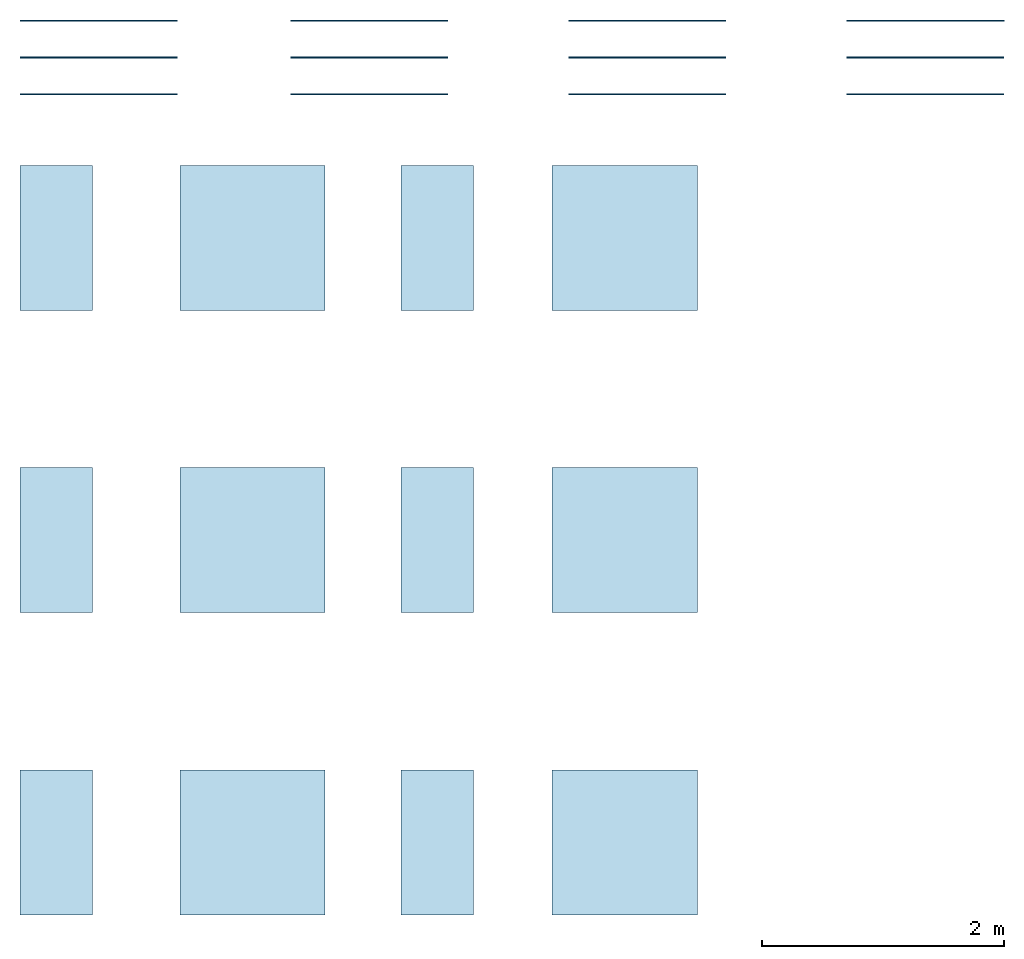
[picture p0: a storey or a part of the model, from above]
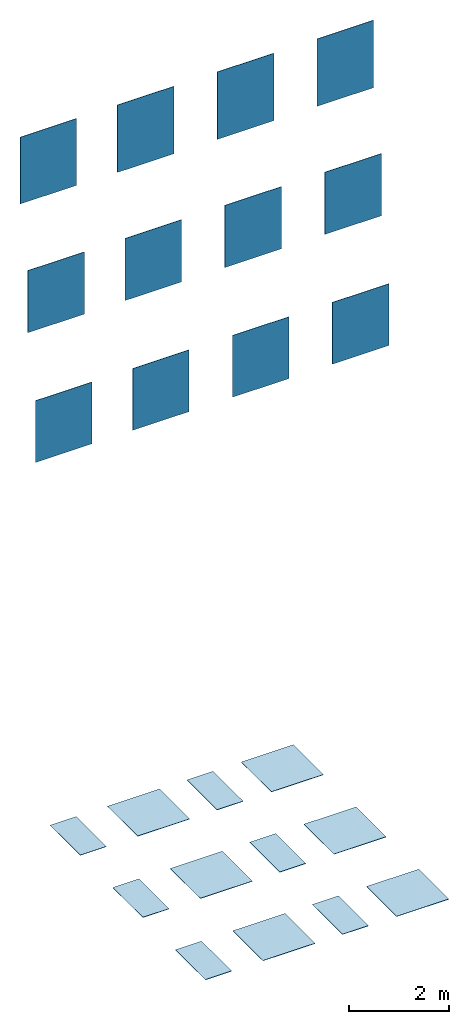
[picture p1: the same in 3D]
Properties of the parts of a building model (IFC2X3)

# File
Description: ViewDefinition [CoordinationView_V2.0], RevitIdentifiers [VersionGUID: 359dbaa7-ac9f-4176-8c9c-8c6b3bc34025, NumberOfSaves: 262], CoordinateReference [CoordinateBase: Shared Coordinates, ProjectSite: Internal]
File name: Project Number
Time: 2024-11-27T16:13:28+01:00
Written by: ODA SDAI 24.3
Made in: Autodesk Revit 24.1.11.26 (ENU) - IFC 24.1.11.26

# IfcProject, Project Number
LongName: Refin-Blended; Phase: Project Status

# IfcSite, Default
RefLatitude: 51, 30, 0, 549316; RefLongitude: 0, -7, -34, -450321; RefElevation: 0 mm

# IfcBuilding
Pset_BuildingCommon - NumberOfStoreys: 1

# IfcBuildingStorey: Level:Circle Head - Project Datum (2)
Pset_AirSideSystemInformation - sets with these values: 2
Name | LongName = Name | Elevation (mm)
Level 0 | Level 0 | 0
Level 1 | Level 1 | 4000

# IfcSlab: Floor:Floor_Tiles_Refin-Cera-Scaglie-Fumo-Cerasilk-120x120 RG00, Floor:Floor_Tiles_Refin-Cera-Scaglie-Fumo-Cerasilk-120x120 RG00:347123
In: Level 0
Type - PredefinedType: FLOOR; Material: Cera-Scaglie-Fumo-Cerasilk-120x120 RG00 9 mm, <Unnamed> 1 mm
Type - Pset_ConcreteElementGeneral - FireRating: INERT
Type - Pset_ElementShading - Color: LIGHT GREY
Type - Pset_FireRatingProperties - SurfaceSpreadOfFlame: INERT
Type - Pset_ManufacturerOccurrence - BarCode: N/A; SerialNumber: N/A
Type - Pset_ManufacturerTypeInformation - ArticleNumber: RG00; ModelReference: RG00; ModelLabel: SCAGLIE FUMO CERASILK R 120X120; Manufacturer: info@refin.it; ProductionYear: N/A
Type - Pset_PrecastConcreteElementGeneral - SerialNumber: N/A
Type - Pset_ProductRequirements - Name: Cera_Scaglie_Fumo_Cerasilk_120X120 R; Category: Pr_35_93_96_19:Ceramic tiles
Type - Pset_QuantityTakeOff - Reference: N/A
Type - Pset_ReinforcementBarPitchOfSlab - Description: PORCELAIN STONEWARE TILE; Reference: N/A
Type - Pset_SlabCommon - Reference: N/A; IsExternal: no; AcousticRating: N/A; FireRating: INERT; SurfaceSpreadOfFlame: INERT
Type - Pset_Warranty - WarrantyContent: N/A; Exclusions: N/A
Pset_QuantityTakeOff - sets with these values: 2
Pset_SlabCommon - LoadBearing: no; PitchAngle: 0 deg

# IfcSlab: Floor:Floor_Tiles_Refin-Cera-Scaglie-Fumo-Cerasilk-60x120 RF40, Floor:Floor_Tiles_Refin-Cera-Scaglie-Fumo-Cerasilk-60x120 RF40:304668
In: Level 0
Type - PredefinedType: FLOOR; Material: Cera-Scaglie-Fumo-Cerasilk-60x120 RF40 9 mm, <Unnamed> 1 mm
Type - Pset_ConcreteElementGeneral - FireRating: INERT
Type - Pset_ElementShading - Color: LIGHT GREY
Type - Pset_FireRatingProperties - SurfaceSpreadOfFlame: INERT
Type - Pset_ManufacturerOccurrence - BarCode: N/A; SerialNumber: N/A
Type - Pset_ManufacturerTypeInformation - ArticleNumber: RF40; ModelReference: RF40; ModelLabel: SCAGLIE FUMO CERASILK R 60X120; Manufacturer: info@refin.it; ProductionYear: N/A
Type - Pset_PrecastConcreteElementGeneral - SerialNumber: N/A
Type - Pset_ProductRequirements - Name: Cera_Scaglie_Fumo_Cerasilk_60X120 R; Category: Pr_35_93_96_19:Ceramic tiles
Type - Pset_QuantityTakeOff - Reference: N/A
Type - Pset_ReinforcementBarPitchOfSlab - Description: PORCELAIN STONEWARE TILE; Reference: N/A
Type - Pset_SlabCommon - Reference: N/A; IsExternal: no; AcousticRating: N/A; FireRating: INERT; SurfaceSpreadOfFlame: INERT
Type - Pset_Warranty - WarrantyContent: N/A; Exclusions: N/A
Pset_QuantityTakeOff - sets with these values: 2
Pset_SlabCommon - LoadBearing: no; PitchAngle: 0 deg

# IfcSlab: Floor:Floor_Tiles_Refin-Cera-Scaglie-Fumo-Matt-Pro-120x120 RG03, Floor:Floor_Tiles_Refin-Cera-Scaglie-Fumo-Matt-Pro-120x120 RG03:347572
In: Level 0
Type - PredefinedType: FLOOR; Material: Cera-Scaglie-Fumo-Matt-Pro-120x120 RG03 9 mm, <Unnamed> 1 mm
Type - Pset_ConcreteElementGeneral - FireRating: INERT
Type - Pset_ElementShading - Color: LIGHT GREY
Type - Pset_FireRatingProperties - SurfaceSpreadOfFlame: INERT
Type - Pset_ManufacturerOccurrence - BarCode: N/A; SerialNumber: N/A
Type - Pset_ManufacturerTypeInformation - ArticleNumber: RG03; ModelReference: RG03; ModelLabel: SCAGLIE FUMO MATT-PRO R 120X120; Manufacturer: info@refin.it; ProductionYear: N/A
Type - Pset_PrecastConcreteElementGeneral - SerialNumber: N/A
Type - Pset_ProductRequirements - Name: Cera_Scaglie_Fumo_Matt_Pro_120X120 R; Category: Pr_35_93_96_19:Ceramic tiles
Type - Pset_QuantityTakeOff - Reference: N/A
Type - Pset_ReinforcementBarPitchOfSlab - Description: PORCELAIN STONEWARE TILE; Reference: N/A
Type - Pset_SlabCommon - Reference: N/A; IsExternal: no; AcousticRating: N/A; FireRating: INERT; SurfaceSpreadOfFlame: INERT
Type - Pset_Warranty - WarrantyContent: N/A; Exclusions: N/A
Pset_QuantityTakeOff - sets with these values: 2
Pset_SlabCommon - LoadBearing: no; PitchAngle: 0 deg

# IfcSlab: Floor:Floor_Tiles_Refin-Cera-Scaglie-Fumo-Matt-Pro-60x120 RG06, Floor:Floor_Tiles_Refin-Cera-Scaglie-Fumo-Matt-Pro-60x120 RG06:347314
In: Level 0
Type - PredefinedType: FLOOR; Material: Cera-Scaglie-Fumo-Matt-Pro-60x120 RG06 9 mm, <Unnamed> 1 mm
Type - Pset_ConcreteElementGeneral - FireRating: INERT
Type - Pset_ElementShading - Color: LIGHT GREY
Type - Pset_FireRatingProperties - SurfaceSpreadOfFlame: INERT
Type - Pset_ManufacturerOccurrence - BarCode: N/A; SerialNumber: N/A
Type - Pset_ManufacturerTypeInformation - ArticleNumber: RG06; ModelReference: RG06; ModelLabel: SCAGLIE FUMO MATT-PRO R 60X120; Manufacturer: info@refin.it; ProductionYear: N/A
Type - Pset_PrecastConcreteElementGeneral - SerialNumber: N/A
Type - Pset_ProductRequirements - Name: Cera_Scaglie_Fumo_Matt_Pro_60X120 R; Category: Pr_35_93_96_19:Ceramic tiles
Type - Pset_QuantityTakeOff - Reference: N/A
Type - Pset_ReinforcementBarPitchOfSlab - Description: PORCELAIN STONEWARE TILE; Reference: N/A
Type - Pset_SlabCommon - Reference: N/A; IsExternal: no; AcousticRating: N/A; FireRating: INERT; SurfaceSpreadOfFlame: INERT
Type - Pset_Warranty - WarrantyContent: N/A; Exclusions: N/A
Pset_QuantityTakeOff - sets with these values: 2
Pset_SlabCommon - LoadBearing: no; PitchAngle: 0 deg

# IfcSlab: Floor:Floor_Tiles_Refin-Cera-Scaglie-Incenso-Cerasilk-120x120 RG01, Floor:Floor_Tiles_Refin-Cera-Scaglie-Incenso-Cerasilk-120x120 RG01:348038
In: Level 0
Type - PredefinedType: FLOOR; Material: Cera-Scaglie-Incenso-Cerasilk-120x120 RG01 9 mm, <Unnamed> 1 mm
Type - Pset_ConcreteElementGeneral - FireRating: INERT
Type - Pset_ElementShading - Color: BEIGE
Type - Pset_FireRatingProperties - SurfaceSpreadOfFlame: INERT
Type - Pset_ManufacturerOccurrence - BarCode: N/A; SerialNumber: N/A
Type - Pset_ManufacturerTypeInformation - ArticleNumber: RG01; ModelReference: RG01; ModelLabel: SCAGLIE INCENSO CERASILK R 120X120; Manufacturer: info@refin.it; ProductionYear: N/A
Type - Pset_PrecastConcreteElementGeneral - SerialNumber: N/A
Type - Pset_ProductRequirements - Name: Cera_Scaglie_Incenso_Cerasilk_120X120 R; Category: Pr_35_93_96_19:Ceramic tiles
Type - Pset_QuantityTakeOff - Reference: N/A
Type - Pset_ReinforcementBarPitchOfSlab - Description: PORCELAIN STONEWARE TILE; Reference: N/A
Type - Pset_SlabCommon - Reference: N/A; IsExternal: no; AcousticRating: N/A; FireRating: INERT; SurfaceSpreadOfFlame: INERT
Type - Pset_Warranty - WarrantyContent: N/A; Exclusions: N/A
Pset_QuantityTakeOff - sets with these values: 2
Pset_SlabCommon - LoadBearing: no; PitchAngle: 0 deg

# IfcSlab: Floor:Floor_Tiles_Refin-Cera-Scaglie-Incenso-Cerasilk-60x120 RF41, Floor:Floor_Tiles_Refin-Cera-Scaglie-Incenso-Cerasilk-60x120 RF41:347870
In: Level 0
Type - PredefinedType: FLOOR; Material: Cera-Scaglie-Incenso-Cerasilk-60x120 RF41 9 mm, <Unnamed> 1 mm
Type - Pset_ConcreteElementGeneral - FireRating: INERT
Type - Pset_ElementShading - Color: BEIGE
Type - Pset_FireRatingProperties - SurfaceSpreadOfFlame: INERT
Type - Pset_ManufacturerOccurrence - BarCode: N/A; SerialNumber: N/A
Type - Pset_ManufacturerTypeInformation - ArticleNumber: RF41; ModelReference: RF41; ModelLabel: SCAGLIE INCENSO CERASILK R 60X120; Manufacturer: info@refin.it; ProductionYear: N/A
Type - Pset_PrecastConcreteElementGeneral - SerialNumber: N/A
Type - Pset_ProductRequirements - Name: Cera_Scaglie_Incenso_Cerasilk_60X120 R; Category: Pr_35_93_96_19:Ceramic tiles
Type - Pset_QuantityTakeOff - Reference: N/A
Type - Pset_ReinforcementBarPitchOfSlab - Description: PORCELAIN STONEWARE TILE; Reference: N/A
Type - Pset_SlabCommon - Reference: N/A; IsExternal: no; AcousticRating: N/A; FireRating: INERT; SurfaceSpreadOfFlame: INERT
Type - Pset_Warranty - WarrantyContent: N/A; Exclusions: N/A
Pset_QuantityTakeOff - sets with these values: 2
Pset_SlabCommon - LoadBearing: no; PitchAngle: 0 deg

# IfcSlab: Floor:Floor_Tiles_Refin-Cera-Scaglie-Incenso-Matt-Pro-120x120 RG04, Floor:Floor_Tiles_Refin-Cera-Scaglie-Incenso-Matt-Pro-120x120 RG04:348478
In: Level 0
Type - PredefinedType: FLOOR; Material: Cera-Scaglie-Incenso-Matt-Pro-120x120 RG04 9 mm, <Unnamed> 1 mm
Type - Pset_ConcreteElementGeneral - FireRating: INERT
Type - Pset_ElementShading - Color: BEIGE
Type - Pset_FireRatingProperties - SurfaceSpreadOfFlame: INERT
Type - Pset_ManufacturerOccurrence - BarCode: N/A; SerialNumber: N/A
Type - Pset_ManufacturerTypeInformation - ArticleNumber: RG04; ModelReference: RG04; ModelLabel: SCAGLIE INCENSO MATT-PRO R 120X120; Manufacturer: info@refin.it; ProductionYear: N/A
Type - Pset_PrecastConcreteElementGeneral - SerialNumber: N/A
Type - Pset_ProductRequirements - Name: Cera_Scaglie_Incenso_Matt_Pro_120X120 R; Category: Pr_35_93_96_19:Ceramic tiles
Type - Pset_QuantityTakeOff - Reference: N/A
Type - Pset_ReinforcementBarPitchOfSlab - Description: PORCELAIN STONEWARE TILE; Reference: N/A
Type - Pset_SlabCommon - Reference: N/A; IsExternal: no; AcousticRating: N/A; FireRating: INERT; SurfaceSpreadOfFlame: INERT
Type - Pset_Warranty - WarrantyContent: N/A; Exclusions: N/A
Pset_QuantityTakeOff - sets with these values: 2
Pset_SlabCommon - LoadBearing: no; PitchAngle: 0 deg

# IfcSlab: Floor:Floor_Tiles_Refin-Cera-Scaglie-Incenso-Matt-Pro-60x120 RG07, Floor:Floor_Tiles_Refin-Cera-Scaglie-Incenso-Matt-Pro-60x120 RG07:348269
In: Level 0
Type - PredefinedType: FLOOR; Material: Cera-Scaglie-Incenso-Matt-Pro-60x120 RG07 9 mm, <Unnamed> 1 mm
Type - Pset_ConcreteElementGeneral - FireRating: INERT
Type - Pset_ElementShading - Color: BEIGE
Type - Pset_FireRatingProperties - SurfaceSpreadOfFlame: INERT
Type - Pset_ManufacturerOccurrence - BarCode: N/A; SerialNumber: N/A
Type - Pset_ManufacturerTypeInformation - ArticleNumber: RG07; ModelReference: RG07; ModelLabel: SCAGLIE INCENSO MATT-PRO R 60X120; Manufacturer: info@refin.it; ProductionYear: N/A
Type - Pset_PrecastConcreteElementGeneral - SerialNumber: N/A
Type - Pset_ProductRequirements - Name: Cera_Scaglie_Incenso_Matt_Pro_60X120 R; Category: Pr_35_93_96_19:Ceramic tiles
Type - Pset_QuantityTakeOff - Reference: N/A
Type - Pset_ReinforcementBarPitchOfSlab - Description: PORCELAIN STONEWARE TILE; Reference: N/A
Type - Pset_SlabCommon - Reference: N/A; IsExternal: no; AcousticRating: N/A; FireRating: INERT; SurfaceSpreadOfFlame: INERT
Type - Pset_Warranty - WarrantyContent: N/A; Exclusions: N/A
Pset_QuantityTakeOff - sets with these values: 2
Pset_SlabCommon - LoadBearing: no; PitchAngle: 0 deg

# IfcSlab: Floor:Floor_Tiles_Refin-Cera-Scaglie-Multicolor-Cerasilk-120x120 RG02, Floor:Floor_Tiles_Refin-Cera-Scaglie-Multicolor-Cerasilk-120x120 RG02:348824
In: Level 0
Type - PredefinedType: FLOOR; Material: Cera-Scaglie-Multicolor-Cerasilk-120x120 RG02 9 mm, <Unnamed> 1 mm
Type - Pset_ConcreteElementGeneral - FireRating: INERT
Type - Pset_ElementShading - Color: MIX
Type - Pset_FireRatingProperties - SurfaceSpreadOfFlame: INERT
Type - Pset_ManufacturerOccurrence - BarCode: N/A; SerialNumber: N/A
Type - Pset_ManufacturerTypeInformation - ArticleNumber: RF42; ModelReference: RF42; ModelLabel: SCAGLIE MULTICOLOR CERASILK R 60X120; Manufacturer: info@refin.it; ProductionYear: N/A
Type - Pset_PrecastConcreteElementGeneral - SerialNumber: N/A
Type - Pset_ProductRequirements - Name: Cera_Scaglie_Multicolor_Cerasilk_60X120 R; Category: Pr_35_93_96_19:Ceramic tiles
Type - Pset_QuantityTakeOff - Reference: N/A
Type - Pset_ReinforcementBarPitchOfSlab - Description: PORCELAIN STONEWARE TILE; Reference: N/A
Type - Pset_SlabCommon - Reference: N/A; IsExternal: no; AcousticRating: N/A; FireRating: INERT; SurfaceSpreadOfFlame: INERT
Type - Pset_Warranty - WarrantyContent: N/A; Exclusions: N/A
Pset_QuantityTakeOff - sets with these values: 2
Pset_SlabCommon - LoadBearing: no; PitchAngle: 0 deg

# IfcSlab: Floor:Floor_Tiles_Refin-Cera-Scaglie-Multicolor-Cerasilk-60x120 RF42, Floor:Floor_Tiles_Refin-Cera-Scaglie-Multicolor-Cerasilk-60x120 RF42:348685
In: Level 0
Type - PredefinedType: FLOOR; Material: Cera-Scaglie-Multicolor-Cerasilk-60x120 RF42 9 mm, <Unnamed> 1 mm
Type - Pset_ConcreteElementGeneral - FireRating: INERT
Type - Pset_ElementShading - Color: MIX
Type - Pset_FireRatingProperties - SurfaceSpreadOfFlame: INERT
Type - Pset_ManufacturerOccurrence - BarCode: N/A; SerialNumber: N/A
Type - Pset_ManufacturerTypeInformation - ArticleNumber: RF42; ModelReference: RF42; ModelLabel: SCAGLIE MULTICOLOR CERASILK R 60X120; Manufacturer: info@refin.it; ProductionYear: N/A
Type - Pset_PrecastConcreteElementGeneral - SerialNumber: N/A
Type - Pset_ProductRequirements - Name: Cera_Scaglie_Multicolor_Cerasilk_60X120 R; Category: Pr_35_93_96_19:Ceramic tiles
Type - Pset_QuantityTakeOff - Reference: N/A
Type - Pset_ReinforcementBarPitchOfSlab - Description: PORCELAIN STONEWARE TILE; Reference: N/A
Type - Pset_SlabCommon - Reference: N/A; IsExternal: no; AcousticRating: N/A; FireRating: INERT; SurfaceSpreadOfFlame: INERT
Type - Pset_Warranty - WarrantyContent: N/A; Exclusions: N/A
Pset_QuantityTakeOff - sets with these values: 2
Pset_SlabCommon - LoadBearing: no; PitchAngle: 0 deg

# IfcSlab: Floor:Floor_Tiles_Refin-Cera-Scaglie-Multicolor-Matt-Pro-120x120 RG05, Floor:Floor_Tiles_Refin-Cera-Scaglie-Multicolor-Matt-Pro-120x120 RG05:349887
In: Level 0
Type - PredefinedType: FLOOR; Material: Cera-Scaglie-Multicolor-Matt-Pro-120x120 RG05 9 mm, <Unnamed> 1 mm
Type - Pset_ConcreteElementGeneral - FireRating: INERT
Type - Pset_ElementShading - Color: MIX
Type - Pset_FireRatingProperties - SurfaceSpreadOfFlame: INERT
Type - Pset_ManufacturerOccurrence - BarCode: N/A; SerialNumber: N/A
Type - Pset_ManufacturerTypeInformation - ArticleNumber: RG05; ModelReference: RG05; ModelLabel: SCAGLIE MULTICOLOR MATT-PRO R 120X120; Manufacturer: info@refin.it; ProductionYear: N/A
Type - Pset_PrecastConcreteElementGeneral - SerialNumber: N/A
Type - Pset_ProductRequirements - Name: Cera_Scaglie_Multicolor_Matt_Pro_120X120 R; Category: Pr_35_93_96_19:Ceramic tiles
Type - Pset_QuantityTakeOff - Reference: N/A
Type - Pset_ReinforcementBarPitchOfSlab - Description: PORCELAIN STONEWARE TILE; Reference: N/A
Type - Pset_SlabCommon - Reference: N/A; IsExternal: no; AcousticRating: N/A; FireRating: INERT; SurfaceSpreadOfFlame: INERT
Type - Pset_Warranty - WarrantyContent: N/A; Exclusions: N/A
Pset_QuantityTakeOff - sets with these values: 2
Pset_SlabCommon - LoadBearing: no; PitchAngle: 0 deg

# IfcSlab: Floor:Floor_Tiles_Refin-Cera-Scaglie-Multicolor-Matt-Pro-60x120 RG08, Floor:Floor_Tiles_Refin-Cera-Scaglie-Multicolor-Matt-Pro-60x120 RG08:349735
In: Level 0
Type - PredefinedType: FLOOR; Material: Cera-Scaglie-Multicolor-Matt-Pro-60x120 RG08 9 mm, <Unnamed> 1 mm
Type - Pset_ConcreteElementGeneral - FireRating: INERT
Type - Pset_ElementShading - Color: MIX
Type - Pset_FireRatingProperties - SurfaceSpreadOfFlame: INERT
Type - Pset_ManufacturerOccurrence - BarCode: N/A; SerialNumber: N/A
Type - Pset_ManufacturerTypeInformation - ArticleNumber: RG08; ModelReference: RG08; ModelLabel: SCAGLIE MULTICOLOR MATT-PRO R 60X120; Manufacturer: info@refin.it; ProductionYear: N/A
Type - Pset_PrecastConcreteElementGeneral - SerialNumber: N/A
Type - Pset_ProductRequirements - Name: Cera_Scaglie_Multicolor_Matt_Pro_60X120 R; Category: Pr_35_93_96_19:Ceramic tiles
Type - Pset_QuantityTakeOff - Reference: N/A
Type - Pset_ReinforcementBarPitchOfSlab - Description: PORCELAIN STONEWARE TILE; Reference: N/A
Type - Pset_SlabCommon - Reference: N/A; IsExternal: no; AcousticRating: N/A; FireRating: INERT; SurfaceSpreadOfFlame: INERT
Type - Pset_Warranty - WarrantyContent: N/A; Exclusions: N/A
Pset_QuantityTakeOff - sets with these values: 2
Pset_SlabCommon - LoadBearing: no; PitchAngle: 0 deg

# IfcWallStandardCase: Basic Wall:Wall_Tiles_Refin-Cera-Scaglie-Fumo-Cerasilk-120x120 RG00, Basic Wall:Wall_Tiles_Refin-Cera-Scaglie-Fumo-Cerasilk-120x120 RG00:333696
In: Level 0
Type - PredefinedType: STANDARD; Material: <Unnamed> 1 mm, Cera-Scaglie-Fumo-Cerasilk-120x120 RG00 9 mm
Type - Pset_ElementShading - Color: LIGHT GREY
Type - Pset_FireRatingProperties - SurfaceSpreadOfFlame: INERT
Type - Pset_ManufacturerOccurrence - BarCode: N/A; SerialNumber: N/A
Type - Pset_ManufacturerTypeInformation - ArticleNumber: RG00; ModelReference: RG00; ModelLabel: SCAGLIE FUMO CERASILK R 120X120; Manufacturer: info@refin.it; ProductionYear: N/A
Type - Pset_PrecastConcreteElementGeneral - SerialNumber: N/A
Type - Pset_ProductRequirements - Name: Cera_Scaglie_Fumo_Cerasilk_120X120 R; Category: Pr_35_93_96_19:Ceramic tiles
Type - Pset_QuantityTakeOff - Reference: N/A
Type - Pset_ReinforcementBarPitchOfWall - Description: PORCELAIN STONEWARE TILE; Reference: N/A
Type - Pset_WallCommon - Reference: N/A; IsExternal: no; AcousticRating: N/A; SurfaceSpreadOfFlame: INERT
Type - Pset_Warranty - WarrantyContent: N/A; Exclusions: N/A
Pset_QuantityTakeOff - sets with these values: 2
Pset_WallCommon - LoadBearing: no; ExtendToStructure: no

# IfcWallStandardCase: Basic Wall:Wall_Tiles_Refin-Cera-Scaglie-Fumo-Cerasilk-60x120 RF40, Basic Wall:Wall_Tiles_Refin-Cera-Scaglie-Fumo-Cerasilk-60x120 RF40:334895
In: Level 0
Type - PredefinedType: STANDARD; Material: <Unnamed> 1 mm, Cera-Scaglie-Fumo-Cerasilk-60x120 RF40 9 mm
Type - Pset_ElementShading - Color: LIGHT GREY
Type - Pset_FireRatingProperties - SurfaceSpreadOfFlame: INERT
Type - Pset_ManufacturerOccurrence - BarCode: N/A; SerialNumber: N/A
Type - Pset_ManufacturerTypeInformation - ArticleNumber: RF40; ModelReference: RF40; ModelLabel: SCAGLIE FUMO CERASILK R 60X120; Manufacturer: info@refin.it; ProductionYear: N/A
Type - Pset_PrecastConcreteElementGeneral - SerialNumber: N/A
Type - Pset_ProductRequirements - Name: Cera_Scaglie_Fumo_Cerasilk_60X120 R; Category: Pr_35_93_96_19:Ceramic tiles
Type - Pset_QuantityTakeOff - Reference: N/A
Type - Pset_ReinforcementBarPitchOfWall - Description: PORCELAIN STONEWARE TILE; Reference: N/A
Type - Pset_WallCommon - Reference: N/A; IsExternal: no; AcousticRating: N/A; SurfaceSpreadOfFlame: INERT
Type - Pset_Warranty - WarrantyContent: N/A; Exclusions: N/A
Pset_QuantityTakeOff - sets with these values: 2
Pset_WallCommon - LoadBearing: no; ExtendToStructure: no

# IfcWallStandardCase: Basic Wall:Wall_Tiles_Refin-Cera-Scaglie-Fumo-Matt-Pro-120x120 RG03, Basic Wall:Wall_Tiles_Refin-Cera-Scaglie-Fumo-Matt-Pro-120x120 RG03:341158
In: Level 0
Type - PredefinedType: STANDARD; Material: <Unnamed> 1 mm, Cera-Scaglie-Fumo-Matt-Pro-120x120 RG03 9 mm
Type - Pset_ElementShading - Color: LIGHT GREY
Type - Pset_FireRatingProperties - SurfaceSpreadOfFlame: INERT
Type - Pset_ManufacturerOccurrence - BarCode: N/A; SerialNumber: N/A
Type - Pset_ManufacturerTypeInformation - ArticleNumber: RG03; ModelReference: RG03; ModelLabel: SCAGLIE FUMO MATT-PRO R 120X120; Manufacturer: info@refin.it; ProductionYear: N/A
Type - Pset_PrecastConcreteElementGeneral - SerialNumber: N/A
Type - Pset_ProductRequirements - Name: Cera_Scaglie_Fumo_Matt_Pro_120X120 R; Category: Pr_35_93_96_19:Ceramic tiles
Type - Pset_QuantityTakeOff - Reference: N/A
Type - Pset_ReinforcementBarPitchOfWall - Description: PORCELAIN STONEWARE TILE; Reference: N/A
Type - Pset_WallCommon - Reference: N/A; IsExternal: no; AcousticRating: N/A; SurfaceSpreadOfFlame: INERT
Type - Pset_Warranty - WarrantyContent: N/A; Exclusions: N/A
Pset_QuantityTakeOff - sets with these values: 2
Pset_WallCommon - LoadBearing: no; ExtendToStructure: no

# IfcWallStandardCase: Basic Wall:Wall_Tiles_Refin-Cera-Scaglie-Fumo-Matt-Pro-60x120 RG06, Basic Wall:Wall_Tiles_Refin-Cera-Scaglie-Fumo-Matt-Pro-60x120 RG06:334553
In: Level 0
Type - PredefinedType: STANDARD; Material: <Unnamed> 1 mm, Cera-Scaglie-Fumo-Matt-Pro-60x120 RG06 9 mm
Type - Pset_ElementShading - Color: LIGHT GREY
Type - Pset_FireRatingProperties - SurfaceSpreadOfFlame: INERT
Type - Pset_ManufacturerOccurrence - BarCode: N/A; SerialNumber: N/A
Type - Pset_ManufacturerTypeInformation - ArticleNumber: RG06; ModelReference: RG06; ModelLabel: SCAGLIE FUMO MATT-PRO R 60X120; Manufacturer: info@refin.it; ProductionYear: N/A
Type - Pset_PrecastConcreteElementGeneral - SerialNumber: N/A
Type - Pset_ProductRequirements - Name: Cera_Scaglie_Fumo_Matt_Pro_60X120 R; Category: Pr_35_93_96_19:Ceramic tiles
Type - Pset_QuantityTakeOff - Reference: N/A
Type - Pset_ReinforcementBarPitchOfWall - Description: PORCELAIN STONEWARE TILE; Reference: N/A
Type - Pset_WallCommon - Reference: N/A; IsExternal: no; AcousticRating: N/A; SurfaceSpreadOfFlame: INERT
Type - Pset_Warranty - WarrantyContent: N/A; Exclusions: N/A
Pset_QuantityTakeOff - sets with these values: 2
Pset_WallCommon - LoadBearing: no; ExtendToStructure: no

# IfcWallStandardCase: Basic Wall:Wall_Tiles_Refin-Cera-Scaglie-Incenso-Cerasilk-120x120 RG01, Basic Wall:Wall_Tiles_Refin-Cera-Scaglie-Incenso-Cerasilk-120x120 RG01:348158
In: Level 0
Type - PredefinedType: STANDARD; Material: <Unnamed> 1 mm, Cera-Scaglie-Incenso-Cerasilk-120x120 RG01 9 mm
Type - Pset_ElementShading - Color: BEIGE
Type - Pset_FireRatingProperties - SurfaceSpreadOfFlame: INERT
Type - Pset_ManufacturerOccurrence - BarCode: N/A; SerialNumber: N/A
Type - Pset_ManufacturerTypeInformation - ArticleNumber: RG01; ModelReference: RG01; ModelLabel: SCAGLIE INCENSO CERASILK R 120X120; Manufacturer: info@refin.it; ProductionYear: N/A
Type - Pset_PrecastConcreteElementGeneral - SerialNumber: N/A
Type - Pset_ProductRequirements - Name: Cera_Scaglie_Incenso_Cerasilk_120X120 R; Category: Pr_35_93_96_19:Ceramic tiles
Type - Pset_QuantityTakeOff - Reference: N/A
Type - Pset_ReinforcementBarPitchOfWall - Description: PORCELAIN STONEWARE TILE; Reference: N/A
Type - Pset_WallCommon - Reference: N/A; IsExternal: no; AcousticRating: N/A; SurfaceSpreadOfFlame: INERT
Type - Pset_Warranty - WarrantyContent: N/A; Exclusions: N/A
Pset_QuantityTakeOff - sets with these values: 2
Pset_WallCommon - LoadBearing: no; ExtendToStructure: no

# IfcWallStandardCase: Basic Wall:Wall_Tiles_Refin-Cera-Scaglie-Incenso-Cerasilk-60x120 RF41, Basic Wall:Wall_Tiles_Refin-Cera-Scaglie-Incenso-Cerasilk-60x120 RF41:335038
In: Level 0
Type - PredefinedType: STANDARD; Material: <Unnamed> 1 mm, Cera-Scaglie-Incenso-Cerasilk-60x120 RF41 9 mm
Type - Pset_ElementShading - Color: BEIGE
Type - Pset_FireRatingProperties - SurfaceSpreadOfFlame: INERT
Type - Pset_ManufacturerOccurrence - BarCode: N/A; SerialNumber: N/A
Type - Pset_ManufacturerTypeInformation - ArticleNumber: RF41; ModelReference: RF41; ModelLabel: SCAGLIE INCENSO CERASILK R 60X120; Manufacturer: info@refin.it; ProductionYear: N/A
Type - Pset_PrecastConcreteElementGeneral - SerialNumber: N/A
Type - Pset_ProductRequirements - Name: Cera_Scaglie_Incenso_Cerasilk_60X120 R; Category: Pr_35_93_96_19:Ceramic tiles
Type - Pset_QuantityTakeOff - Reference: N/A
Type - Pset_ReinforcementBarPitchOfWall - Description: PORCELAIN STONEWARE TILE; Reference: N/A
Type - Pset_WallCommon - Reference: N/A; IsExternal: no; AcousticRating: N/A; SurfaceSpreadOfFlame: INERT
Type - Pset_Warranty - WarrantyContent: N/A; Exclusions: N/A
Pset_QuantityTakeOff - sets with these values: 2
Pset_WallCommon - LoadBearing: no; ExtendToStructure: no

# IfcWallStandardCase: Basic Wall:Wall_Tiles_Refin-Cera-Scaglie-Incenso-Matt-Pro-120x120 RG04, Basic Wall:Wall_Tiles_Refin-Cera-Scaglie-Incenso-Matt-Pro-120x120 RG04:340784
In: Level 0
Type - PredefinedType: STANDARD; Material: <Unnamed> 1 mm, Cera-Scaglie-Incenso-Matt-Pro-120x120 RG04 9 mm
Type - Pset_ElementShading - Color: BEIGE
Type - Pset_FireRatingProperties - SurfaceSpreadOfFlame: INERT
Type - Pset_ManufacturerOccurrence - BarCode: N/A; SerialNumber: N/A
Type - Pset_ManufacturerTypeInformation - ArticleNumber: RG04; ModelReference: RG04; ModelLabel: SCAGLIE INCENSO MATT-PRO R 120X120; Manufacturer: info@refin.it; ProductionYear: N/A
Type - Pset_PrecastConcreteElementGeneral - SerialNumber: N/A
Type - Pset_ProductRequirements - Name: Cera_Scaglie_Incenso_Matt_Pro_120X120 R; Category: Pr_35_93_96_19:Ceramic tiles
Type - Pset_QuantityTakeOff - Reference: N/A
Type - Pset_ReinforcementBarPitchOfWall - Description: PORCELAIN STONEWARE TILE; Reference: N/A
Type - Pset_WallCommon - Reference: N/A; IsExternal: no; AcousticRating: N/A; SurfaceSpreadOfFlame: INERT
Type - Pset_Warranty - WarrantyContent: N/A; Exclusions: N/A
Pset_QuantityTakeOff - sets with these values: 2
Pset_WallCommon - LoadBearing: no; ExtendToStructure: no

# IfcWallStandardCase: Basic Wall:Wall_Tiles_Refin-Cera-Scaglie-Incenso-Matt-Pro-60x120 RG07, Basic Wall:Wall_Tiles_Refin-Cera-Scaglie-Incenso-Matt-Pro-60x120 RG07:348395
In: Level 0
Type - PredefinedType: STANDARD; Material: <Unnamed> 1 mm, Cera-Scaglie-Incenso-Matt-Pro-60x120 RG07 9 mm
Type - Pset_ElementShading - Color: BEIGE
Type - Pset_FireRatingProperties - SurfaceSpreadOfFlame: INERT
Type - Pset_ManufacturerOccurrence - BarCode: N/A; SerialNumber: N/A
Type - Pset_ManufacturerTypeInformation - ArticleNumber: RG07; ModelReference: RG07; ModelLabel: SCAGLIE INCENSO MATT-PRO R 60X120; Manufacturer: info@refin.it; ProductionYear: N/A
Type - Pset_PrecastConcreteElementGeneral - SerialNumber: N/A
Type - Pset_ProductRequirements - Name: Cera_Scaglie_Incenso_Matt_Pro_60X120 R; Category: Pr_35_93_96_19:Ceramic tiles
Type - Pset_QuantityTakeOff - Reference: N/A
Type - Pset_ReinforcementBarPitchOfWall - Description: PORCELAIN STONEWARE TILE; Reference: N/A
Type - Pset_WallCommon - Reference: N/A; IsExternal: no; AcousticRating: N/A; SurfaceSpreadOfFlame: INERT
Type - Pset_Warranty - WarrantyContent: N/A; Exclusions: N/A
Pset_QuantityTakeOff - sets with these values: 2
Pset_WallCommon - LoadBearing: no; ExtendToStructure: no

# IfcWallStandardCase: Basic Wall:Wall_Tiles_Refin-Cera-Scaglie-Multicolor-Cerasilk-120x120 RG02, Basic Wall:Wall_Tiles_Refin-Cera-Scaglie-Multicolor-Cerasilk-120x120 RG02:342594
In: Level 0
Type - PredefinedType: STANDARD; Material: <Unnamed> 1 mm, Cera-Scaglie-Multicolor-Cerasilk-120x120 RG02 9 mm
Type - Pset_ElementShading - Color: MIX
Type - Pset_FireRatingProperties - SurfaceSpreadOfFlame: INERT
Type - Pset_ManufacturerOccurrence - BarCode: N/A; SerialNumber: N/A
Type - Pset_ManufacturerTypeInformation - ArticleNumber: RG02; ModelReference: RG02; ModelLabel: SCAGLIE MULTICOLOR CERASILK R 120X120; Manufacturer: info@refin.it; ProductionYear: N/A
Type - Pset_PrecastConcreteElementGeneral - SerialNumber: N/A
Type - Pset_ProductRequirements - Name: Cera_Scaglie_Multicolor_Cerasilk_120X120 R; Category: Pr_35_93_96_19:Ceramic tiles
Type - Pset_QuantityTakeOff - Reference: N/A
Type - Pset_ReinforcementBarPitchOfWall - Description: PORCELAIN STONEWARE TILE; Reference: N/A
Type - Pset_WallCommon - Reference: N/A; IsExternal: no; AcousticRating: N/A; SurfaceSpreadOfFlame: INERT
Type - Pset_Warranty - WarrantyContent: N/A; Exclusions: N/A
Pset_QuantityTakeOff - sets with these values: 2
Pset_WallCommon - LoadBearing: no; ExtendToStructure: no

# IfcWallStandardCase: Basic Wall:Wall_Tiles_Refin-Cera-Scaglie-Multicolor-Cerasilk-60x120 RF42, Basic Wall:Wall_Tiles_Refin-Cera-Scaglie-Multicolor-Cerasilk-60x120 RF42:336183
In: Level 0
Type - PredefinedType: STANDARD; Material: <Unnamed> 1 mm, Cera-Scaglie-Multicolor-Cerasilk-60x120 RF42 9 mm
Type - Pset_ElementShading - Color: MIX
Type - Pset_FireRatingProperties - SurfaceSpreadOfFlame: INERT
Type - Pset_ManufacturerOccurrence - BarCode: N/A; SerialNumber: N/A
Type - Pset_ManufacturerTypeInformation - ArticleNumber: RF42; ModelReference: RF42; ModelLabel: SCAGLIE MULTICOLOR CERASILK R 60X120; Manufacturer: info@refin.it; ProductionYear: N/A
Type - Pset_PrecastConcreteElementGeneral - SerialNumber: N/A
Type - Pset_ProductRequirements - Name: Cera_Scaglie_Multicolor_Cerasilk_60X120 R; Category: Pr_35_93_96_19:Ceramic tiles
Type - Pset_QuantityTakeOff - Reference: N/A
Type - Pset_ReinforcementBarPitchOfWall - Description: PORCELAIN STONEWARE TILE; Reference: N/A
Type - Pset_WallCommon - Reference: N/A; IsExternal: no; AcousticRating: N/A; SurfaceSpreadOfFlame: INERT
Type - Pset_Warranty - WarrantyContent: N/A; Exclusions: N/A
Pset_QuantityTakeOff - sets with these values: 2
Pset_WallCommon - LoadBearing: no; ExtendToStructure: no

# IfcWallStandardCase: Basic Wall:Wall_Tiles_Refin-Cera-Scaglie-Multicolor-Matt-Pro-120x120 RG05, Basic Wall:Wall_Tiles_Refin-Cera-Scaglie-Multicolor-Matt-Pro-120x120 RG05:342942
In: Level 0
Type - PredefinedType: STANDARD; Material: <Unnamed> 1 mm, Cera-Scaglie-Multicolor-Matt-Pro-120x120 RG05 9 mm
Type - Pset_ElementShading - Color: MIX
Type - Pset_FireRatingProperties - SurfaceSpreadOfFlame: INERT
Type - Pset_ManufacturerOccurrence - BarCode: N/A; SerialNumber: N/A
Type - Pset_ManufacturerTypeInformation - ArticleNumber: RG05; ModelReference: RG05; ModelLabel: SCAGLIE MULTICOLOR MATT-PRO R 120X120; Manufacturer: info@refin.it; ProductionYear: N/A
Type - Pset_PrecastConcreteElementGeneral - SerialNumber: N/A
Type - Pset_ProductRequirements - Name: Cera_Scaglie_Multicolor_Matt_Pro_120X120 R; Category: Pr_35_93_96_19:Ceramic tiles
Type - Pset_QuantityTakeOff - Reference: N/A
Type - Pset_ReinforcementBarPitchOfWall - Description: PORCELAIN STONEWARE TILE; Reference: N/A
Type - Pset_WallCommon - Reference: N/A; IsExternal: no; AcousticRating: N/A; SurfaceSpreadOfFlame: INERT
Type - Pset_Warranty - WarrantyContent: N/A; Exclusions: N/A
Pset_QuantityTakeOff - sets with these values: 2
Pset_WallCommon - LoadBearing: no; ExtendToStructure: no

# IfcWallStandardCase: Basic Wall:Wall_Tiles_Refin-Cera-Scaglie-Multicolor-Matt-Pro-60x120 RG08, Basic Wall:Wall_Tiles_Refin-Cera-Scaglie-Multicolor-Matt-Pro-60x120 RG08:342842
In: Level 0
Type - PredefinedType: STANDARD; Material: <Unnamed> 1 mm, Cera-Scaglie-Multicolor-Matt-Pro-60x120 RG08 9 mm
Type - Pset_ElementShading - Color: MIX
Type - Pset_FireRatingProperties - SurfaceSpreadOfFlame: INERT
Type - Pset_ManufacturerOccurrence - BarCode: N/A; SerialNumber: N/A
Type - Pset_ManufacturerTypeInformation - ArticleNumber: RG08; ModelReference: RG08; ModelLabel: SCAGLIE MULTICOLOR MATT-PRO R 60X120; Manufacturer: info@refin.it; ProductionYear: N/A
Type - Pset_PrecastConcreteElementGeneral - SerialNumber: N/A
Type - Pset_ProductRequirements - Name: Cera_Scaglie_Multicolor_Matt_Pro_60X120 R; Category: Pr_35_93_96_19:Ceramic tiles
Type - Pset_QuantityTakeOff - Reference: N/A
Type - Pset_ReinforcementBarPitchOfWall - Description: PORCELAIN STONEWARE TILE; Reference: N/A
Type - Pset_WallCommon - Reference: N/A; IsExternal: no; AcousticRating: N/A; SurfaceSpreadOfFlame: INERT
Type - Pset_Warranty - WarrantyContent: N/A; Exclusions: N/A
Pset_QuantityTakeOff - sets with these values: 2
Pset_WallCommon - LoadBearing: no; ExtendToStructure: no
